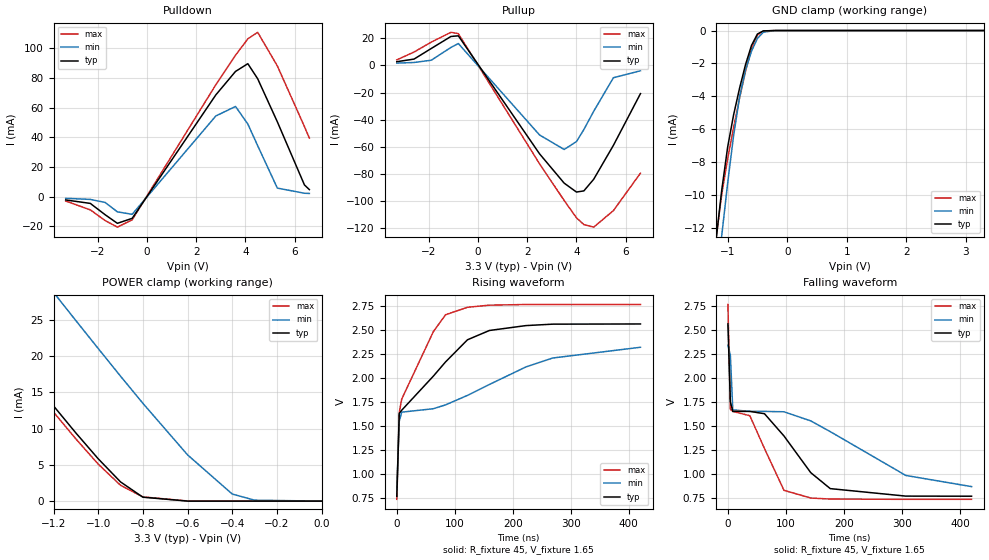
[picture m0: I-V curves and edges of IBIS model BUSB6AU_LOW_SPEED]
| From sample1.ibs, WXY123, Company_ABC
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|   Model BUSB6AU_LOW_SPEED
[Model]   BUSB6AU_LOW_SPEED
Model_type   I/O
Polarity   Non-Inverting
Enable   Active-Low
Vinl   = 0.8V
Vinh   = 2.0V
Vmeas   = 1.65V
Cref   = 50pF
Vref   = 0V
Rref   = 1Mohms
C_comp   8.08pF  NA   NA
[Temperature Range]   25   125   0
[Voltage Range]   3.3V   3.0V   3.6V
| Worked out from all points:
|   slope of the pulldown table from 0 to 0.495 V, typ, clamps not added: 38.9 ohm
|   slope of the pullup table from 0 to 0.495 V, typ, clamps not added: 36.2 ohm
|   GND clamp passes 1 mA (typ) near -0.61 V on its own axis
|   POWER clamp passes 1 mA (typ) near -0.82 V on its own axis
|   rising waveform, R_fixture 45, V_fixture 1.65: 20-80 % time 87.4ns typ, 188ns min, 51.3ns max; typ from 0.766 V to 2.56 V
|   falling waveform, R_fixture 45, V_fixture 1.65: 20-80 % time 127ns typ, 246ns min, 69.5ns max; typ from 2.56 V to 0.766 V
[Pulldown]
| voltage   I(typ)   I(min)   I(max)
-3.3V     -2.175mA   -1.098mA   -2.889mA
-2.3V     -4.517mA   -1.814mA   -8.883mA
-1.7V     -12.12mA   -3.861mA   -16.05mA
-1.2V     -17.94mA   -10.2mA    -20.52mA
-600mV    -14.59mA   -11.86mA   -15.59mA
2.8V      68.63mA    54.42mA    75.48mA
3.6V      84.45mA    60.83mA    95.38mA
4.1V      89.66mA    48.98mA    106.4mA
4.5V      79.51mA    34.39mA    110.8mA
5.3V      50.45mA    5.792mA    88.13mA
6.4V      7.952mA    2.337mA    47.28mA
6.6V      4.788mA    2.202mA    39.53mA
[Pullup]
| voltage   I(typ)   I(min)   I(max)
-3.3V     2.742mA    1.709mA    4.1mA
-2.6V     4.668mA    2.159mA    9.864mA
-1.9V     12.5mA     3.841mA    17.17mA
-1.1V     21.36mA    13.27mA    24.41mA
-800mV    21.83mA    16.14mA    23.44mA
2.5V      -65.22mA   -51.31mA   -72.57mA
3.5V      -86.84mA   -62mA      -99.61mA
4V        -93.4mA    -56.18mA   -112.4mA
4.3V      -92.55mA   -47.3mA    -117.4mA
4.7V      -83.96mA   -33.82mA   -119.3mA
5.5V      -58.98mA   -9.085mA   -107.1mA
6.6V      -20.82mA   -3.932mA   -79.48mA
[GND Clamp]
|  voltage   I(typ)   I(min)   I(max)
-3.3V     -94.56mA   -96.98mA   -94.2mA
-1.2V     -12.91mA   -15.91mA   -12.77mA
-1.1V     -9.716mA   -12.49mA   -9.98mA
-1V       -7.084mA   -9.275mA   -7.793mA
-900mV    -5.125mA   -6.385mA   -5.889mA
-800mV    -3.507mA   -4.046mA   -4.108mA
-700mV    -2.075mA   -2.405mA   -2.475mA
-600mV    -908.1uA   -1.263mA   -1.114mA
-500mV    -211.6uA   -477.8uA   -270uA
-400mV    -20.77uA   -100uA     -27.36uA
-200mV    -40.88nA   -1.036uA   -76.73nA
3.3V      305.1pA    442.9nA    224.7pA
[POWER Clamp]
|  voltage   I(typ)   I(min)   I(max)
-3.3V     97.03mA    112.9mA    96.21mA
-1.6V     28.68mA    44.57mA    27.8mA
-1.5V     24.75mA    40.6mA     23.86mA
-1.2V     13.14mA    28.8mA     12.28mA
-1.1V     9.406mA    24.91mA    8.587mA
-1V       5.845mA    21.06mA    5.108mA
-900mV    2.654mA    17.24mA    2.187mA
-800mV    542.7uA    13.5mA     582.6uA
-600mV    7.296uA    6.387mA    20.98uA
-400mV    116.5nA    981.9uA    409.1nA
-300mV    14.02nA    132uA      52.45nA
0V        305.1pA    442.9nA    434.6pA
| variable   typ   min   max
[Ramp]
dV/dt_r  1.07779V/87.4472ns   0.888133V/188.194ns   1.2193V/51.2698ns
dV/dt_f  1.07779V/126.984ns   0.884956V/245.501ns   1.2193V/69.4684ns
R_load   = 50
[Rising Waveform]
R_fixture   = 45
V_fixture   = 1.65
V_fixture_min   = 1.65
V_fixture_max   = 1.65
| time   V(typ)   V(min)   V(max)
0s        766.4mV    839.5mV    733.9mV
4.2ns     1.63V      1.547V     1.64V
8.4ns     1.663V     1.643V     1.779V
63ns      2.019V     1.679V     2.483V
84ns      2.167V     1.719V     2.659V
121.8ns   2.398V     1.818V     2.737V
159.6ns   2.495V     1.932V     2.759V
222.6ns   2.546V     2.115V     2.766V
268.8ns   2.561V     2.208V     2.766V
420ns     2.563V     2.32V      2.766V
[Falling Waveform]
R_fixture   = 45
V_fixture   = 1.65
V_fixture_min   = 1.65
V_fixture_max   = 1.65
| time   V(typ)   V(min)   V(max)
0s        2.563V     2.341V     2.766V
4.2ns     1.752V     2.239V     1.673V
8.4ns     1.651V     1.667V     1.651V
37.8ns    1.651V     1.651V     1.606V
63ns      1.627V     1.651V     1.264V
96.6ns    1.395V     1.647V     828mV
142.8ns   1.012V     1.552V     747.5mV
176.4ns   845.6mV    1.44V      736.8mV
306.6ns   767.5mV    983.1mV    733.9mV
420ns     766.4mV    866.6mV    733.9mV
